VERSION 5.8 ;
BUSBITCHARS "[]" ;
DIVIDERCHAR "/" ;

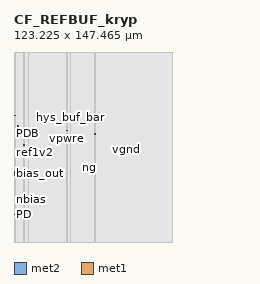
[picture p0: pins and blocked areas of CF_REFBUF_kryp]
MACRO CF_REFBUF_kryp
  ORIGIN 0 0 ;
  SIZE 123.225 BY 147.465 ;
  PIN out
    DIRECTION OUTPUT ;
    USE SIGNAL ;
    PORT
      LAYER met2 ;
        RECT 62.275 83.675 63.345 84.32 ;
    END
  END out
  PIN bias_out
    DIRECTION OUTPUT ;
    USE SIGNAL ;
    PORT
      LAYER met2 ;
        RECT 0.46 51.675 0.845 54.715 ;
    END
  END bias_out
  PIN ng
    DIRECTION INPUT ;
    USE SIGNAL ;
    PORT
      LAYER met1 ;
        RECT 58.33 58.095 58.675 58.29 ;
    END
  END ng
  PIN PD
    DIRECTION INPUT ;
    USE SIGNAL ;
    PORT
      LAYER met1 ;
        RECT 0.23 20.995 1.21 21.27 ;
    END
  END PD
  PIN nbias
    DIRECTION INPUT ;
    USE SIGNAL ;
    PORT
      LAYER met1 ;
        RECT 1.23 32.81 1.5 32.98 ;
    END
  END nbias
  PIN ref1v2
    DIRECTION INPUT ;
    USE SIGNAL ;
    PORT
      LAYER met2 ;
        RECT 7.095 75.21 7.79 75.5 ;
    END
  END ref1v2
  PIN vpwre
    DIRECTION INPUT ;
    USE SIGNAL ;
    PORT
      LAYER met1 ;
        RECT 51.51 94.485 51.635 94.615 ;
      LAYER met2 ;
        RECT 41 86.23 41.225 86.545 ;
      LAYER met1 ;
        RECT 4.14 97.435 4.395 97.62 ;
    END
  END vpwre
  PIN vpbe
    DIRECTION INPUT ;
    USE SIGNAL ;
    PORT
      LAYER met1 ;
        RECT 52.82 57.24 55.615 57.72 ;
      LAYER met2 ;
        RECT 43.665 86.23 43.89 86.545 ;
      LAYER met1 ;
        RECT 49.305 94.665 49.435 94.79 ;
        RECT 0.63 97.885 0.83 98.005 ;
    END
  END vpbe
  PIN vpwr
    DIRECTION INPUT ;
    USE SIGNAL ;
    PORT
      LAYER met1 ;
        RECT 12.02 97.595 12.255 97.755 ;
    END
  END vpwr
  PIN vpb
    DIRECTION INPUT ;
    USE SIGNAL ;
    PORT
      LAYER met1 ;
        RECT 13.61 97.53 13.77 97.685 ;
    END
  END vpb
  PIN vgnd
    DIRECTION INPUT ;
    USE SIGNAL ;
    PORT
      LAYER met1 ;
        RECT 85.545 70.96 88.965 72.115 ;
        RECT 49.92 99.83 50.09 99.99 ;
        RECT 12.495 94.955 12.67 95.09 ;
    END
  END vgnd
  PIN vnb
    DIRECTION INPUT ;
    USE SIGNAL ;
    PORT
      LAYER met1 ;
        RECT 49.275 98.855 49.44 99.025 ;
        RECT 10.13 94.765 10.305 94.915 ;
    END
  END vnb
  PIN PDB
    DIRECTION INPUT ;
    USE SIGNAL ;
    PORT
      LAYER met1 ;
        RECT 3 89.995 3.15 90.265 ;
    END
  END PDB
  PIN hys_buf_bar
    DIRECTION INPUT ;
    USE SIGNAL ;
    PORT
      LAYER met1 ;
        RECT 44.04 96.68 44.16 96.81 ;
    END
  END hys_buf_bar
  PIN swon
    DIRECTION INPUT ;
    USE SIGNAL ;
    PORT
      LAYER met1 ;
        RECT 24.605 93.005 24.74 93.13 ;
    END
  END swon
  PIN switchoff
    DIRECTION OUTPUT ;
    USE SIGNAL ;
    PORT
      LAYER met2 ;
        RECT 11.02 93.535 11.3 93.67 ;
    END
  END switchoff
  OBS
    LAYER li1 ;
      RECT 0 0 123.225 147.465 ;
    LAYER met1 ;
      RECT 0 0 0.23 147.465 ;
      RECT 0.23 0 0.63 20.995 ;
      RECT 0.23 21.27 0.63 147.465 ;
      RECT 0.63 0 0.83 20.995 ;
      RECT 0.63 21.27 0.83 97.885 ;
      RECT 0.63 98.005 0.83 147.465 ;
      RECT 0.83 0 1.21 20.995 ;
      RECT 0.83 21.27 1.21 147.465 ;
      RECT 1.21 0 1.23 147.465 ;
      RECT 1.23 0 1.5 32.81 ;
      RECT 1.23 32.98 1.5 147.465 ;
      RECT 1.5 0 3 147.465 ;
      RECT 3 0 3.15 89.995 ;
      RECT 3 90.265 3.15 147.465 ;
      RECT 3.15 0 4.14 147.465 ;
      RECT 4.14 0 4.395 97.435 ;
      RECT 4.14 97.62 4.395 147.465 ;
      RECT 4.395 0 10.13 147.465 ;
      RECT 10.13 0 10.305 94.765 ;
      RECT 10.13 94.915 10.305 147.465 ;
      RECT 10.305 0 12.02 147.465 ;
      RECT 12.02 0 12.255 97.595 ;
      RECT 12.02 97.755 12.255 147.465 ;
      RECT 12.255 0 12.495 147.465 ;
      RECT 12.495 0 12.67 94.955 ;
      RECT 12.495 95.09 12.67 147.465 ;
      RECT 12.67 0 13.61 147.465 ;
      RECT 13.61 0 13.77 97.53 ;
      RECT 13.61 97.685 13.77 147.465 ;
      RECT 13.77 0 24.605 147.465 ;
      RECT 24.605 0 24.74 93.005 ;
      RECT 24.605 93.13 24.74 147.465 ;
      RECT 24.74 0 44.04 147.465 ;
      RECT 44.04 0 44.16 96.68 ;
      RECT 44.04 96.81 44.16 147.465 ;
      RECT 44.16 0 49.275 147.465 ;
      RECT 49.275 0 49.305 98.855 ;
      RECT 49.275 99.025 49.305 147.465 ;
      RECT 49.305 0 49.435 94.665 ;
      RECT 49.305 94.79 49.435 98.855 ;
      RECT 49.305 99.025 49.435 147.465 ;
      RECT 49.435 0 49.44 98.855 ;
      RECT 49.435 99.025 49.44 147.465 ;
      RECT 49.44 0 49.92 147.465 ;
      RECT 49.92 0 50.09 99.83 ;
      RECT 49.92 99.99 50.09 147.465 ;
      RECT 50.09 0 51.51 147.465 ;
      RECT 51.51 0 51.635 94.485 ;
      RECT 51.51 94.615 51.635 147.465 ;
      RECT 51.635 0 52.82 147.465 ;
      RECT 52.82 0 55.615 57.24 ;
      RECT 52.82 57.72 55.615 147.465 ;
      RECT 55.615 0 58.33 147.465 ;
      RECT 58.33 0 58.675 58.095 ;
      RECT 58.33 58.29 58.675 147.465 ;
      RECT 58.675 0 85.545 147.465 ;
      RECT 85.545 0 88.965 70.96 ;
      RECT 85.545 72.115 88.965 147.465 ;
      RECT 88.965 0 123.225 147.465 ;
    LAYER met2 ;
      RECT 0 0 0.46 147.465 ;
      RECT 0.46 0 0.845 51.675 ;
      RECT 0.46 54.715 0.845 147.465 ;
      RECT 0.845 0 7.095 147.465 ;
      RECT 7.095 0 7.79 75.21 ;
      RECT 7.095 75.5 7.79 147.465 ;
      RECT 7.79 0 11.02 147.465 ;
      RECT 11.02 0 11.3 93.535 ;
      RECT 11.02 93.67 11.3 147.465 ;
      RECT 11.3 0 41 147.465 ;
      RECT 41 0 41.225 86.23 ;
      RECT 41 86.545 41.225 147.465 ;
      RECT 41.225 0 43.665 147.465 ;
      RECT 43.665 0 43.89 86.23 ;
      RECT 43.665 86.545 43.89 147.465 ;
      RECT 43.89 0 62.275 147.465 ;
      RECT 62.275 0 63.345 83.675 ;
      RECT 62.275 84.32 63.345 147.465 ;
      RECT 63.345 0 123.225 147.465 ;
  END
END CF_REFBUF_kryp

END LIBRARY
